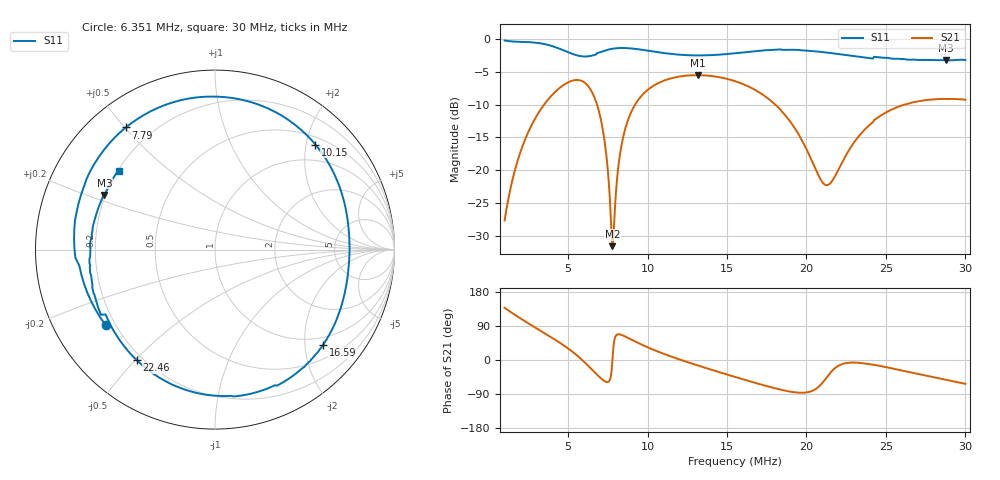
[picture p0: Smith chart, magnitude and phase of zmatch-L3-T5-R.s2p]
# HZ S RI R 50
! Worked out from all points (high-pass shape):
!   505 points, 1 MHz to 30 MHz, reference 50 ohm
!   highest |S21| = -5.52 dB at 13.14 MHz (marker M1); lowest = -31.6 dB at 7.79 MHz (marker M2)
!   |S21| within 3 dB of the highest: 3.996 MHz to 6.582 MHz (2.585 MHz wide, 48.9 % of centre); 9.674 MHz to 17.26 MHz (7.59 MHz wide, 56.4 % of centre)
!   lowest |S11| = -3.3 dB at 28.79 MHz (marker M3), VSWR 5.39, Z = 9.77 + j11.3 ohm
!   |S11| at or under -10 dB: nowhere
!   S12 and S22 are empty: the file has one direction only
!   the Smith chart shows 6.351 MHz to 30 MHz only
!   S11 on the Smith chart (normalised r, x): 6.351 MHz: 0.16, -0.31; 7.79 MHz: 0.11, +0.50; 10.15 MHz: 0.64, +2.18; 16.59 MHz: 0.80, -2.41; 22.46 MHz: 0.18, -0.51; 30 MHz: 0.21, +0.34
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1000000  -0.5609 0.7967  -0.0307 0.0277  0 0  0 0
2380960  0.3165 0.8929  -0.0306 0.1796  0 0  0 0
3761920  0.8814 0.1783  0.1501 0.3144  0 0  0 0
4337320  0.8178 -0.2463  0.2678 0.3119  0 0  0 0
4970260  0.4903 -0.6259  0.3978 0.2416  0 0  0 0
5833360  -0.2329 -0.7006  0.4798 0.0162  0 0  0 0
6351220  -0.6083 -0.4223  0.3993 -0.1376  0 0  0 0
7214320  -0.7461 0.3061  0.1142 -0.1543  0 0  0 0
7789720  -0.4967 0.6808  0.0263 0.000292  0 0  0 0
8192500  -0.2546 0.8141  0.0433 0.1066  0 0  0 0
8537740  -0.0495 0.8518  0.0887 0.1741  0 0  0 0
1.014886e7  0.5598 0.5852  0.3627 0.2157  0 0  0 0
1.066672e7  0.6436 0.4619  0.4273 0.1718  0 0  0 0
1.314094e7  0.7497 -0.00841  0.5135 -0.1296  0 0  0 0
1.550008e7  0.6866 -0.3657  0.3394 -0.3352  0 0  0 0
1.659334e7  0.6018 -0.5317  0.2217 -0.3566  0 0  0 0
2.033344e7  -0.0558 -0.8076  0.0166 -0.117  0 0  0 0
2.131162e7  -0.2491 -0.7471  0.0556 -0.053  0 0  0 0
2.246242e7  -0.4349 -0.6167  0.1271 -0.0188  0 0  0 0
2.51668e7  -0.6825 -0.2154  0.265 -0.0976  0 0  0 0
2.879182e7  -0.6159 0.3043  0.2114 -0.2774  0 0  0 0
3.000016e7  -0.5347 0.4373  0.1575 -0.3056  0 0  0 0
